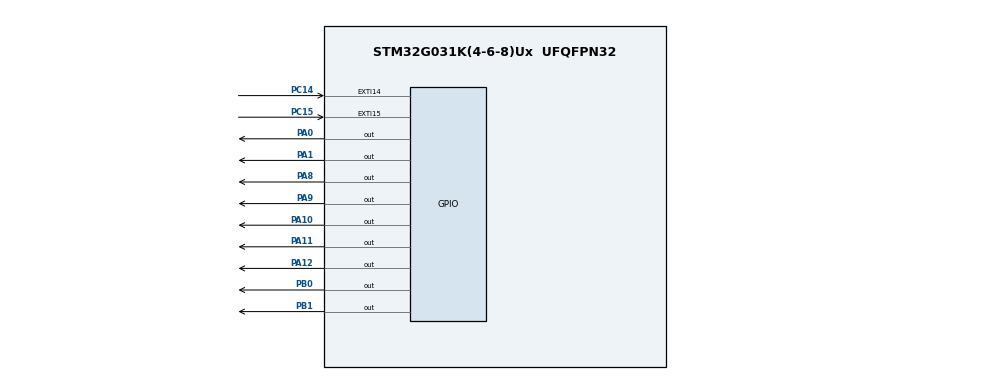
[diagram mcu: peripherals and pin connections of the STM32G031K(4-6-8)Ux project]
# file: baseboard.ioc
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Mcu.Family=STM32G0
Mcu.Name=STM32G031K(4-6-8)Ux
Mcu.Package=UFQFPN32
NVIC.EXTI4_15_IRQn=true\:0\:0\:true\:false\:true\:true\:true\:true
PA0.Signal=GPIO_Output
PA1.Signal=GPIO_Output
PA10.Signal=GPIO_Output
PA11\ [PA9].Signal=GPIO_Output
PA12\ [PA10].Signal=GPIO_Output
PA13.Mode=Serial_Wire
PA13.Signal=SYS_SWDIO
PA14-BOOT0.Mode=Serial_Wire
PA14-BOOT0.Signal=SYS_SWCLK
PA8.Signal=GPIO_Output
PA9.Signal=GPIO_Output
PB0.Signal=GPIO_Output
PB1.Signal=GPIO_Output
PC14-OSC32_IN\ (PC14).Signal=GPXTI14
PC15-OSC32_OUT\ (PC15).Signal=GPXTI15
ProjectManager.HeapSize=0x200
ProjectManager.StackSize=0x400
ProjectManager.TargetToolchain=EWARM V8.50
RCC.ADCFreq_Value=8000000
RCC.AHBFreq_Value=8000000
RCC.CortexFreq_Value=8000000
RCC.EXTERNAL_CLOCK_VALUE=12288000
RCC.HCLKFreq_Value=8000000
RCC.HSE_VALUE=12000000
RCC.HSI_VALUE=16000000
RCC.LSE_VALUE=32768
RCC.PLLM=RCC_PLLM_DIV2
RCC.PLLR=RCC_PLLR_DIV8
RCC.SYSCLKFreq_VALUE=8000000
RCC.SYSCLKSource=RCC_SYSCLKSOURCE_PLLCLK
RCC.VCOOutputFreq_Value=64000000
board=custom

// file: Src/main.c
/* USER CODE BEGIN Header */
/**
  ******************************************************************************
  * @file           : main.c
  * @brief          : Main program body
  ******************************************************************************
  * @attention
  *
  * Copyright (c) 2023 STMicroelectronics.
  * All rights reserved.
  *
  * This software is licensed under terms that can be found in the LICENSE file
  * in the root directory of this software component.
  * If no LICENSE file comes with this software, it is provided AS-IS.
  *
  ******************************************************************************
  */
/* USER CODE END Header */
#include "main.h"

void SystemClock_Config(void);
static void MX_GPIO_Init(void);

int main(void)
{

  /* MCU Configuration--------------------------------------------------------*/

  /* Reset of all peripherals, Initializes the Flash interface and the Systick. */
  HAL_Init();

  /* Configure the system clock */
  SystemClock_Config();

  /* Initialize all configured peripherals */
  MX_GPIO_Init();

  /* Infinite loop */
  while (1)
  {

  }
}

void SystemClock_Config(void)
{
  RCC_OscInitTypeDef RCC_OscInitStruct = {0};
  RCC_ClkInitTypeDef RCC_ClkInitStruct = {0};

  /** Configure the main internal regulator output voltage
  */
  __HAL_PWR_VOLTAGESCALING_CONFIG(PWR_REGULATOR_VOLTAGE_SCALE1);

  /** Initializes the RCC Oscillators according to the specified parameters
  * in the RCC_OscInitTypeDef structure.
  */
  RCC_OscInitStruct.OscillatorType = RCC_OSCILLATORTYPE_HSI;
  RCC_OscInitStruct.HSIState = RCC_HSI_DIV4;
  RCC_OscInitStruct.HSICalibrationValue = RCC_HSICALIBRATION_DEFAULT;
  RCC_OscInitStruct.PLL.PLLState = RCC_PLL_ON;
  RCC_OscInitStruct.PLL.PLLSource = RCC_PLLSOURCE_HSI;
  RCC_OscInitStruct.PLL.PLLMUL = RCC_PLLMUL_4;
  RCC_OscInitStruct.PLL.PLLDIV = RCC_PLLDIV_2;
  if (HAL_RCC_OscConfig(&RCC_OscInitStruct) != HAL_OK)
  {
    Error_Handler();
  }

  /** Initializes the CPU, AHB and APB buses clocks
  */
  RCC_ClkInitStruct.ClockType = RCC_CLOCKTYPE_HCLK|RCC_CLOCKTYPE_SYSCLK
                              |RCC_CLOCKTYPE_PCLK1|RCC_CLOCKTYPE_PCLK2;
  RCC_ClkInitStruct.SYSCLKSource = RCC_SYSCLKSOURCE_PLLCLK;
  RCC_ClkInitStruct.AHBCLKDivider = RCC_SYSCLK_DIV8;
  RCC_ClkInitStruct.APB1CLKDivider = RCC_HCLK_DIV1;
  RCC_ClkInitStruct.APB2CLKDivider = RCC_HCLK_DIV1;

  if (HAL_RCC_ClockConfig(&RCC_ClkInitStruct, FLASH_LATENCY_0) != HAL_OK)
  {
    Error_Handler();
  }
}

static void MX_GPIO_Init(void)
{
  GPIO_InitTypeDef GPIO_InitStruct = {0};

  /* GPIO Ports Clock Enable */
  __HAL_RCC_GPIOC_CLK_ENABLE();
  __HAL_RCC_GPIOA_CLK_ENABLE();
  __HAL_RCC_GPIOB_CLK_ENABLE();

  /*Configure GPIO pin Output Level */
  HAL_GPIO_WritePin(GPIOC, VDDA__EN_Pin|VDDA__ENC15_Pin, GPIO_PIN_RESET);

  /*Configure GPIO pin Output Level */
  HAL_GPIO_WritePin(GPIOA, SW_EN_Pin|SW_IN1_Pin|SW_IN2_Pin|SW_IN3_Pin
                          |SW_IN4_Pin|LED2_Pin|LED1_Pin, GPIO_PIN_RESET);

  /*Configure GPIO pins : VDDA__EN_Pin VDDA__ENC15_Pin */
  GPIO_InitStruct.Pin = VDDA__EN_Pin|VDDA__ENC15_Pin;
  GPIO_InitStruct.Mode = GPIO_MODE_OUTPUT_PP;
  GPIO_InitStruct.Pull = GPIO_NOPULL;
  GPIO_InitStruct.Speed = GPIO_SPEED_FREQ_LOW;
  HAL_GPIO_Init(GPIOC, &GPIO_InitStruct);

  /*Configure GPIO pin : PA0 */
  GPIO_InitStruct.Pin = GPIO_PIN_0;
  GPIO_InitStruct.Mode = GPIO_MODE_ANALOG;
  GPIO_InitStruct.Pull = GPIO_NOPULL;
  HAL_GPIO_Init(GPIOA, &GPIO_InitStruct);

  /*Configure GPIO pins : SW_EN_Pin SW_IN1_Pin SW_IN2_Pin SW_IN3_Pin
                           SW_IN4_Pin LED2_Pin LED1_Pin */
  GPIO_InitStruct.Pin = SW_EN_Pin|SW_IN1_Pin|SW_IN2_Pin|SW_IN3_Pin
                          |SW_IN4_Pin|LED2_Pin|LED1_Pin;
  GPIO_InitStruct.Mode = GPIO_MODE_OUTPUT_PP;
  GPIO_InitStruct.Pull = GPIO_NOPULL;
  GPIO_InitStruct.Speed = GPIO_SPEED_FREQ_LOW;
  HAL_GPIO_Init(GPIOA, &GPIO_InitStruct);

  /*Configure GPIO pin : PB1 */
  GPIO_InitStruct.Pin = GPIO_PIN_1;
  GPIO_InitStruct.Mode = GPIO_MODE_ANALOG;
  GPIO_InitStruct.Pull = GPIO_NOPULL;
  HAL_GPIO_Init(GPIOB, &GPIO_InitStruct);

  /*Configure GPIO pins : FTSW2_Pin FTSW1_Pin */
  GPIO_InitStruct.Pin = FTSW2_Pin|FTSW1_Pin;
  GPIO_InitStruct.Mode = GPIO_MODE_INPUT;
  GPIO_InitStruct.Pull = GPIO_NOPULL;
  HAL_GPIO_Init(GPIOB, &GPIO_InitStruct);

}

void Error_Handler(void)
{
  __disable_irq();
  while (1)
  {
  }
}
